VERSION 5.7 ;
  NOWIREEXTENSIONATPIN ON ;
  DIVIDERCHAR "/" ;
  BUSBITCHARS "[]" ;
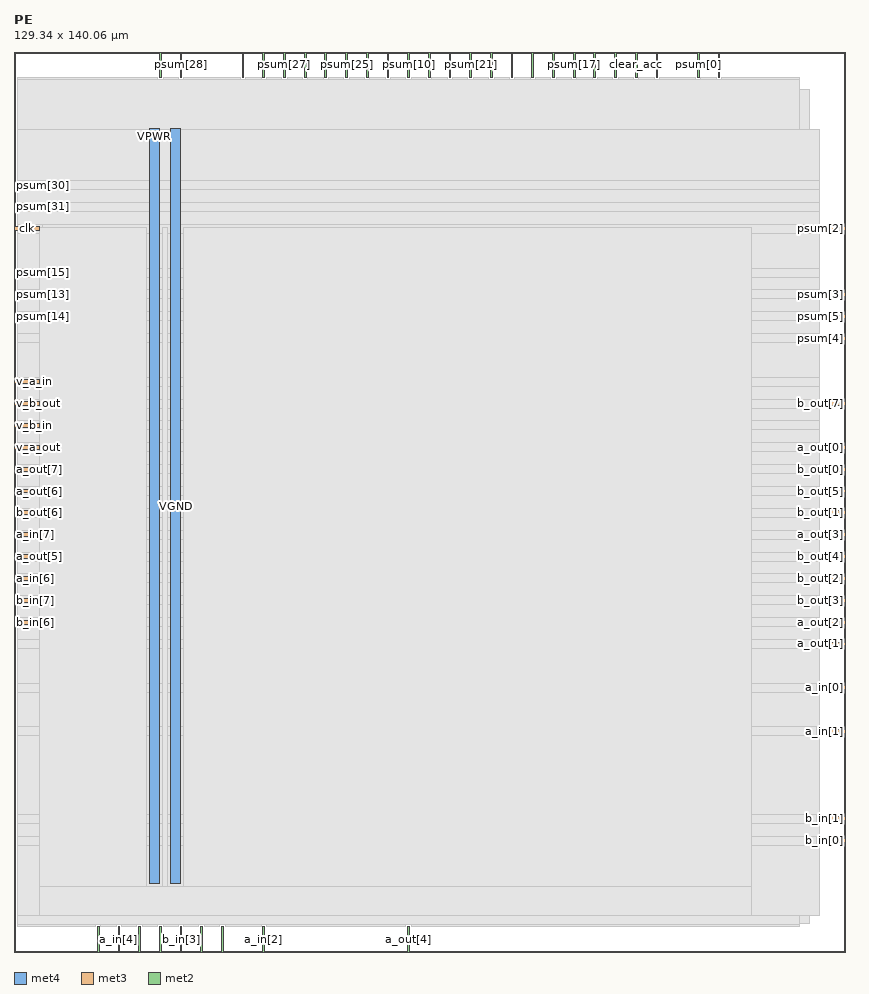
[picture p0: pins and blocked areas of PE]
MACRO PE
  CLASS BLOCK ;
  FOREIGN PE ;
  ORIGIN 0.000 0.000 ;
  SIZE 129.340 BY 140.060 ;
  PIN VGND
    DIRECTION INOUT ;
    USE GROUND ;
    PORT
      LAYER met4 ;
        RECT 24.340 10.640 25.940 128.080 ;
    END
  END VGND
  PIN VPWR
    DIRECTION INOUT ;
    USE POWER ;
    PORT
      LAYER met4 ;
        RECT 21.040 10.640 22.640 128.080 ;
    END
  END VPWR
  PIN a_in[0]
    DIRECTION INPUT ;
    USE SIGNAL ;
    ANTENNAGATEAREA 0.196500 ;
    PORT
      LAYER met3 ;
        RECT 125.340 40.840 129.340 41.440 ;
    END
  END a_in[0]
  PIN a_in[1]
    DIRECTION INPUT ;
    USE SIGNAL ;
    ANTENNAGATEAREA 0.196500 ;
    PORT
      LAYER met3 ;
        RECT 125.340 34.040 129.340 34.640 ;
    END
  END a_in[1]
  PIN a_in[2]
    DIRECTION INPUT ;
    USE SIGNAL ;
    ANTENNAGATEAREA 0.196500 ;
    PORT
      LAYER met2 ;
        RECT 38.730 0.000 39.010 4.000 ;
    END
  END a_in[2]
  PIN a_in[3]
    DIRECTION INPUT ;
    USE SIGNAL ;
    ANTENNAGATEAREA 0.196500 ;
    PORT
      LAYER met2 ;
        RECT 12.970 0.000 13.250 4.000 ;
    END
  END a_in[3]
  PIN a_in[4]
    DIRECTION INPUT ;
    USE SIGNAL ;
    ANTENNAGATEAREA 0.196500 ;
    PORT
      LAYER met2 ;
        RECT 16.190 0.000 16.470 4.000 ;
    END
  END a_in[4]
  PIN a_in[5]
    DIRECTION INPUT ;
    USE SIGNAL ;
    ANTENNAGATEAREA 0.213000 ;
    PORT
      LAYER met2 ;
        RECT 19.410 0.000 19.690 4.000 ;
    END
  END a_in[5]
  PIN a_in[6]
    DIRECTION INPUT ;
    USE SIGNAL ;
    ANTENNAGATEAREA 0.495000 ;
    PORT
      LAYER met3 ;
        RECT 0.000 57.840 4.000 58.440 ;
    END
  END a_in[6]
  PIN a_in[7]
    DIRECTION INPUT ;
    USE SIGNAL ;
    ANTENNAGATEAREA 0.196500 ;
    PORT
      LAYER met3 ;
        RECT 0.000 64.640 4.000 65.240 ;
    END
  END a_in[7]
  PIN a_out[0]
    DIRECTION OUTPUT ;
    USE SIGNAL ;
    ANTENNADIFFAREA 0.445500 ;
    PORT
      LAYER met3 ;
        RECT 125.340 78.240 129.340 78.840 ;
    END
  END a_out[0]
  PIN a_out[1]
    DIRECTION OUTPUT ;
    USE SIGNAL ;
    ANTENNADIFFAREA 0.445500 ;
    PORT
      LAYER met3 ;
        RECT 125.340 47.640 129.340 48.240 ;
    END
  END a_out[1]
  PIN a_out[2]
    DIRECTION OUTPUT ;
    USE SIGNAL ;
    ANTENNADIFFAREA 0.445500 ;
    PORT
      LAYER met3 ;
        RECT 125.340 51.040 129.340 51.640 ;
    END
  END a_out[2]
  PIN a_out[3]
    DIRECTION OUTPUT ;
    USE SIGNAL ;
    ANTENNADIFFAREA 0.445500 ;
    PORT
      LAYER met3 ;
        RECT 125.340 64.640 129.340 65.240 ;
    END
  END a_out[3]
  PIN a_out[4]
    DIRECTION OUTPUT ;
    USE SIGNAL ;
    ANTENNADIFFAREA 0.445500 ;
    PORT
      LAYER met2 ;
        RECT 61.270 0.000 61.550 4.000 ;
    END
  END a_out[4]
  PIN a_out[5]
    DIRECTION OUTPUT ;
    USE SIGNAL ;
    ANTENNADIFFAREA 0.445500 ;
    PORT
      LAYER met3 ;
        RECT 0.000 61.240 4.000 61.840 ;
    END
  END a_out[5]
  PIN a_out[6]
    DIRECTION OUTPUT ;
    USE SIGNAL ;
    ANTENNADIFFAREA 0.445500 ;
    PORT
      LAYER met3 ;
        RECT 0.000 71.440 4.000 72.040 ;
    END
  END a_out[6]
  PIN a_out[7]
    DIRECTION OUTPUT ;
    USE SIGNAL ;
    ANTENNADIFFAREA 0.445500 ;
    PORT
      LAYER met3 ;
        RECT 0.000 74.840 4.000 75.440 ;
    END
  END a_out[7]
  PIN b_in[0]
    DIRECTION INPUT ;
    USE SIGNAL ;
    ANTENNAGATEAREA 0.196500 ;
    PORT
      LAYER met3 ;
        RECT 125.340 17.040 129.340 17.640 ;
    END
  END b_in[0]
  PIN b_in[1]
    DIRECTION INPUT ;
    USE SIGNAL ;
    ANTENNAGATEAREA 0.213000 ;
    PORT
      LAYER met3 ;
        RECT 125.340 20.440 129.340 21.040 ;
    END
  END b_in[1]
  PIN b_in[2]
    DIRECTION INPUT ;
    USE SIGNAL ;
    ANTENNAGATEAREA 0.213000 ;
    PORT
      LAYER met2 ;
        RECT 22.630 0.000 22.910 4.000 ;
    END
  END b_in[2]
  PIN b_in[3]
    DIRECTION INPUT ;
    USE SIGNAL ;
    ANTENNAGATEAREA 0.196500 ;
    PORT
      LAYER met2 ;
        RECT 25.850 0.000 26.130 4.000 ;
    END
  END b_in[3]
  PIN b_in[4]
    DIRECTION INPUT ;
    USE SIGNAL ;
    ANTENNAGATEAREA 0.196500 ;
    PORT
      LAYER met2 ;
        RECT 29.070 0.000 29.350 4.000 ;
    END
  END b_in[4]
  PIN b_in[5]
    DIRECTION INPUT ;
    USE SIGNAL ;
    ANTENNAGATEAREA 0.196500 ;
    PORT
      LAYER met2 ;
        RECT 32.290 0.000 32.570 4.000 ;
    END
  END b_in[5]
  PIN b_in[6]
    DIRECTION INPUT ;
    USE SIGNAL ;
    ANTENNAGATEAREA 0.196500 ;
    PORT
      LAYER met3 ;
        RECT 0.000 51.040 4.000 51.640 ;
    END
  END b_in[6]
  PIN b_in[7]
    DIRECTION INPUT ;
    USE SIGNAL ;
    ANTENNAGATEAREA 0.196500 ;
    PORT
      LAYER met3 ;
        RECT 0.000 54.440 4.000 55.040 ;
    END
  END b_in[7]
  PIN b_out[0]
    DIRECTION OUTPUT ;
    USE SIGNAL ;
    ANTENNADIFFAREA 0.445500 ;
    PORT
      LAYER met3 ;
        RECT 125.340 74.840 129.340 75.440 ;
    END
  END b_out[0]
  PIN b_out[1]
    DIRECTION OUTPUT ;
    USE SIGNAL ;
    ANTENNADIFFAREA 0.445500 ;
    PORT
      LAYER met3 ;
        RECT 125.340 68.040 129.340 68.640 ;
    END
  END b_out[1]
  PIN b_out[2]
    DIRECTION OUTPUT ;
    USE SIGNAL ;
    ANTENNADIFFAREA 0.445500 ;
    PORT
      LAYER met3 ;
        RECT 125.340 57.840 129.340 58.440 ;
    END
  END b_out[2]
  PIN b_out[3]
    DIRECTION OUTPUT ;
    USE SIGNAL ;
    ANTENNADIFFAREA 0.445500 ;
    PORT
      LAYER met3 ;
        RECT 125.340 54.440 129.340 55.040 ;
    END
  END b_out[3]
  PIN b_out[4]
    DIRECTION OUTPUT ;
    USE SIGNAL ;
    ANTENNADIFFAREA 0.445500 ;
    PORT
      LAYER met3 ;
        RECT 125.340 61.240 129.340 61.840 ;
    END
  END b_out[4]
  PIN b_out[5]
    DIRECTION OUTPUT ;
    USE SIGNAL ;
    ANTENNADIFFAREA 0.445500 ;
    PORT
      LAYER met3 ;
        RECT 125.340 71.440 129.340 72.040 ;
    END
  END b_out[5]
  PIN b_out[6]
    DIRECTION OUTPUT ;
    USE SIGNAL ;
    ANTENNADIFFAREA 0.445500 ;
    PORT
      LAYER met3 ;
        RECT 0.000 68.040 4.000 68.640 ;
    END
  END b_out[6]
  PIN b_out[7]
    DIRECTION OUTPUT ;
    USE SIGNAL ;
    ANTENNADIFFAREA 0.445500 ;
    PORT
      LAYER met3 ;
        RECT 125.340 85.040 129.340 85.640 ;
    END
  END b_out[7]
  PIN clear_acc
    DIRECTION INPUT ;
    USE SIGNAL ;
    ANTENNAGATEAREA 0.213000 ;
    PORT
      LAYER met2 ;
        RECT 96.690 136.060 96.970 140.060 ;
    END
  END clear_acc
  PIN clk
    DIRECTION INPUT ;
    USE SIGNAL ;
    ANTENNAGATEAREA 0.852000 ;
    PORT
      LAYER met3 ;
        RECT 0.000 112.240 4.000 112.840 ;
    END
  END clk
  PIN psum[0]
    DIRECTION OUTPUT ;
    USE SIGNAL ;
    ANTENNADIFFAREA 0.445500 ;
    PORT
      LAYER met2 ;
        RECT 106.350 136.060 106.630 140.060 ;
    END
  END psum[0]
  PIN psum[10]
    DIRECTION OUTPUT ;
    USE SIGNAL ;
    ANTENNADIFFAREA 0.445500 ;
    PORT
      LAYER met2 ;
        RECT 61.270 136.060 61.550 140.060 ;
    END
  END psum[10]
  PIN psum[11]
    DIRECTION OUTPUT ;
    USE SIGNAL ;
    ANTENNADIFFAREA 0.445500 ;
    PORT
      LAYER met2 ;
        RECT 48.390 136.060 48.670 140.060 ;
    END
  END psum[11]
  PIN psum[12]
    DIRECTION OUTPUT ;
    USE SIGNAL ;
    ANTENNADIFFAREA 0.445500 ;
    PORT
      LAYER met2 ;
        RECT 38.730 136.060 39.010 140.060 ;
    END
  END psum[12]
  PIN psum[13]
    DIRECTION OUTPUT ;
    USE SIGNAL ;
    ANTENNADIFFAREA 0.445500 ;
    PORT
      LAYER met3 ;
        RECT 0.000 102.040 4.000 102.640 ;
    END
  END psum[13]
  PIN psum[14]
    DIRECTION OUTPUT ;
    USE SIGNAL ;
    ANTENNADIFFAREA 0.445500 ;
    PORT
      LAYER met3 ;
        RECT 0.000 98.640 4.000 99.240 ;
    END
  END psum[14]
  PIN psum[15]
    DIRECTION OUTPUT ;
    USE SIGNAL ;
    ANTENNADIFFAREA 0.445500 ;
    PORT
      LAYER met3 ;
        RECT 0.000 105.440 4.000 106.040 ;
    END
  END psum[15]
  PIN psum[16]
    DIRECTION OUTPUT ;
    USE SIGNAL ;
    ANTENNADIFFAREA 0.445500 ;
    PORT
      LAYER met2 ;
        RECT 93.470 136.060 93.750 140.060 ;
    END
  END psum[16]
  PIN psum[17]
    DIRECTION OUTPUT ;
    USE SIGNAL ;
    ANTENNADIFFAREA 0.445500 ;
    PORT
      LAYER met2 ;
        RECT 87.030 136.060 87.310 140.060 ;
    END
  END psum[17]
  PIN psum[18]
    DIRECTION OUTPUT ;
    USE SIGNAL ;
    ANTENNADIFFAREA 0.445500 ;
    PORT
      LAYER met2 ;
        RECT 90.250 136.060 90.530 140.060 ;
    END
  END psum[18]
  PIN psum[19]
    DIRECTION OUTPUT ;
    USE SIGNAL ;
    ANTENNADIFFAREA 0.445500 ;
    PORT
      LAYER met2 ;
        RECT 80.590 136.060 80.870 140.060 ;
    END
  END psum[19]
  PIN psum[1]
    DIRECTION OUTPUT ;
    USE SIGNAL ;
    ANTENNADIFFAREA 1.336500 ;
    PORT
      LAYER met2 ;
        RECT 109.570 136.060 109.850 140.060 ;
    END
  END psum[1]
  PIN psum[20]
    DIRECTION OUTPUT ;
    USE SIGNAL ;
    ANTENNADIFFAREA 0.445500 ;
    PORT
      LAYER met2 ;
        RECT 67.710 136.060 67.990 140.060 ;
    END
  END psum[20]
  PIN psum[21]
    DIRECTION OUTPUT ;
    USE SIGNAL ;
    ANTENNADIFFAREA 0.445500 ;
    PORT
      LAYER met2 ;
        RECT 70.930 136.060 71.210 140.060 ;
    END
  END psum[21]
  PIN psum[22]
    DIRECTION OUTPUT ;
    USE SIGNAL ;
    ANTENNADIFFAREA 0.445500 ;
    PORT
      LAYER met2 ;
        RECT 64.490 136.060 64.770 140.060 ;
    END
  END psum[22]
  PIN psum[23]
    DIRECTION OUTPUT ;
    USE SIGNAL ;
    ANTENNADIFFAREA 0.445500 ;
    PORT
      LAYER met2 ;
        RECT 58.050 136.060 58.330 140.060 ;
    END
  END psum[23]
  PIN psum[24]
    DIRECTION OUTPUT ;
    USE SIGNAL ;
    ANTENNADIFFAREA 0.445500 ;
    PORT
      LAYER met2 ;
        RECT 54.830 136.060 55.110 140.060 ;
    END
  END psum[24]
  PIN psum[25]
    DIRECTION OUTPUT ;
    USE SIGNAL ;
    ANTENNADIFFAREA 0.445500 ;
    PORT
      LAYER met2 ;
        RECT 51.610 136.060 51.890 140.060 ;
    END
  END psum[25]
  PIN psum[26]
    DIRECTION OUTPUT ;
    USE SIGNAL ;
    ANTENNADIFFAREA 0.445500 ;
    PORT
      LAYER met2 ;
        RECT 35.510 136.060 35.790 140.060 ;
    END
  END psum[26]
  PIN psum[27]
    DIRECTION OUTPUT ;
    USE SIGNAL ;
    ANTENNADIFFAREA 0.445500 ;
    PORT
      LAYER met2 ;
        RECT 41.950 136.060 42.230 140.060 ;
    END
  END psum[27]
  PIN psum[28]
    DIRECTION OUTPUT ;
    USE SIGNAL ;
    ANTENNADIFFAREA 0.445500 ;
    PORT
      LAYER met2 ;
        RECT 25.850 136.060 26.130 140.060 ;
    END
  END psum[28]
  PIN psum[29]
    DIRECTION OUTPUT ;
    USE SIGNAL ;
    ANTENNADIFFAREA 0.445500 ;
    PORT
      LAYER met2 ;
        RECT 22.630 136.060 22.910 140.060 ;
    END
  END psum[29]
  PIN psum[2]
    DIRECTION OUTPUT ;
    USE SIGNAL ;
    ANTENNADIFFAREA 0.445500 ;
    PORT
      LAYER met3 ;
        RECT 125.340 112.240 129.340 112.840 ;
    END
  END psum[2]
  PIN psum[30]
    DIRECTION OUTPUT ;
    USE SIGNAL ;
    ANTENNADIFFAREA 0.445500 ;
    PORT
      LAYER met3 ;
        RECT 0.000 119.040 4.000 119.640 ;
    END
  END psum[30]
  PIN psum[31]
    DIRECTION OUTPUT ;
    USE SIGNAL ;
    ANTENNADIFFAREA 0.445500 ;
    PORT
      LAYER met3 ;
        RECT 0.000 115.640 4.000 116.240 ;
    END
  END psum[31]
  PIN psum[3]
    DIRECTION OUTPUT ;
    USE SIGNAL ;
    ANTENNADIFFAREA 0.445500 ;
    PORT
      LAYER met3 ;
        RECT 125.340 102.040 129.340 102.640 ;
    END
  END psum[3]
  PIN psum[4]
    DIRECTION OUTPUT ;
    USE SIGNAL ;
    ANTENNADIFFAREA 0.445500 ;
    PORT
      LAYER met3 ;
        RECT 125.340 95.240 129.340 95.840 ;
    END
  END psum[4]
  PIN psum[5]
    DIRECTION OUTPUT ;
    USE SIGNAL ;
    ANTENNADIFFAREA 0.445500 ;
    PORT
      LAYER met3 ;
        RECT 125.340 98.640 129.340 99.240 ;
    END
  END psum[5]
  PIN psum[6]
    DIRECTION OUTPUT ;
    USE SIGNAL ;
    ANTENNADIFFAREA 0.445500 ;
    PORT
      LAYER met2 ;
        RECT 99.910 136.060 100.190 140.060 ;
    END
  END psum[6]
  PIN psum[7]
    DIRECTION OUTPUT ;
    USE SIGNAL ;
    ANTENNADIFFAREA 0.445500 ;
    PORT
      LAYER met2 ;
        RECT 83.810 136.060 84.090 140.060 ;
    END
  END psum[7]
  PIN psum[8]
    DIRECTION OUTPUT ;
    USE SIGNAL ;
    ANTENNADIFFAREA 0.445500 ;
    PORT
      LAYER met2 ;
        RECT 77.370 136.060 77.650 140.060 ;
    END
  END psum[8]
  PIN psum[9]
    DIRECTION OUTPUT ;
    USE SIGNAL ;
    ANTENNADIFFAREA 0.445500 ;
    PORT
      LAYER met2 ;
        RECT 74.150 136.060 74.430 140.060 ;
    END
  END psum[9]
  PIN reset
    DIRECTION INPUT ;
    USE SIGNAL ;
    ANTENNAGATEAREA 0.213000 ;
    PORT
      LAYER met2 ;
        RECT 45.170 136.060 45.450 140.060 ;
    END
  END reset
  PIN v_a_in
    DIRECTION INPUT ;
    USE SIGNAL ;
    ANTENNAGATEAREA 0.213000 ;
    PORT
      LAYER met3 ;
        RECT 0.000 88.440 4.000 89.040 ;
    END
  END v_a_in
  PIN v_a_out
    DIRECTION OUTPUT ;
    USE SIGNAL ;
    ANTENNADIFFAREA 0.445500 ;
    PORT
      LAYER met3 ;
        RECT 0.000 78.240 4.000 78.840 ;
    END
  END v_a_out
  PIN v_b_in
    DIRECTION INPUT ;
    USE SIGNAL ;
    ANTENNAGATEAREA 0.213000 ;
    PORT
      LAYER met3 ;
        RECT 0.000 81.640 4.000 82.240 ;
    END
  END v_b_in
  PIN v_b_out
    DIRECTION OUTPUT ;
    USE SIGNAL ;
    ANTENNADIFFAREA 0.445500 ;
    PORT
      LAYER met3 ;
        RECT 0.000 85.040 4.000 85.640 ;
    END
  END v_b_out
  OBS
      LAYER nwell ;
        RECT 5.330 10.795 123.930 128.030 ;
      LAYER li1 ;
        RECT 5.520 10.795 123.740 127.925 ;
      LAYER met1 ;
        RECT 0.530 4.460 123.740 134.260 ;
      LAYER met2 ;
        RECT 0.550 135.780 22.350 136.060 ;
        RECT 23.190 135.780 25.570 136.060 ;
        RECT 26.410 135.780 35.230 136.060 ;
        RECT 36.070 135.780 38.450 136.060 ;
        RECT 39.290 135.780 41.670 136.060 ;
        RECT 42.510 135.780 44.890 136.060 ;
        RECT 45.730 135.780 48.110 136.060 ;
        RECT 48.950 135.780 51.330 136.060 ;
        RECT 52.170 135.780 54.550 136.060 ;
        RECT 55.390 135.780 57.770 136.060 ;
        RECT 58.610 135.780 60.990 136.060 ;
        RECT 61.830 135.780 64.210 136.060 ;
        RECT 65.050 135.780 67.430 136.060 ;
        RECT 68.270 135.780 70.650 136.060 ;
        RECT 71.490 135.780 73.870 136.060 ;
        RECT 74.710 135.780 77.090 136.060 ;
        RECT 77.930 135.780 80.310 136.060 ;
        RECT 81.150 135.780 83.530 136.060 ;
        RECT 84.370 135.780 86.750 136.060 ;
        RECT 87.590 135.780 89.970 136.060 ;
        RECT 90.810 135.780 93.190 136.060 ;
        RECT 94.030 135.780 96.410 136.060 ;
        RECT 97.250 135.780 99.630 136.060 ;
        RECT 100.470 135.780 106.070 136.060 ;
        RECT 106.910 135.780 109.290 136.060 ;
        RECT 110.130 135.780 122.270 136.060 ;
        RECT 0.550 4.280 122.270 135.780 ;
        RECT 0.550 4.000 12.690 4.280 ;
        RECT 13.530 4.000 15.910 4.280 ;
        RECT 16.750 4.000 19.130 4.280 ;
        RECT 19.970 4.000 22.350 4.280 ;
        RECT 23.190 4.000 25.570 4.280 ;
        RECT 26.410 4.000 28.790 4.280 ;
        RECT 29.630 4.000 32.010 4.280 ;
        RECT 32.850 4.000 38.450 4.280 ;
        RECT 39.290 4.000 60.990 4.280 ;
        RECT 61.830 4.000 122.270 4.280 ;
      LAYER met3 ;
        RECT 0.525 120.040 125.340 128.005 ;
        RECT 4.400 118.640 125.340 120.040 ;
        RECT 0.525 116.640 125.340 118.640 ;
        RECT 4.400 115.240 125.340 116.640 ;
        RECT 0.525 113.240 125.340 115.240 ;
        RECT 4.400 111.840 124.940 113.240 ;
        RECT 0.525 106.440 125.340 111.840 ;
        RECT 4.400 105.040 125.340 106.440 ;
        RECT 0.525 103.040 125.340 105.040 ;
        RECT 4.400 101.640 124.940 103.040 ;
        RECT 0.525 99.640 125.340 101.640 ;
        RECT 4.400 98.240 124.940 99.640 ;
        RECT 0.525 96.240 125.340 98.240 ;
        RECT 0.525 94.840 124.940 96.240 ;
        RECT 0.525 89.440 125.340 94.840 ;
        RECT 4.400 88.040 125.340 89.440 ;
        RECT 0.525 86.040 125.340 88.040 ;
        RECT 4.400 84.640 124.940 86.040 ;
        RECT 0.525 82.640 125.340 84.640 ;
        RECT 4.400 81.240 125.340 82.640 ;
        RECT 0.525 79.240 125.340 81.240 ;
        RECT 4.400 77.840 124.940 79.240 ;
        RECT 0.525 75.840 125.340 77.840 ;
        RECT 4.400 74.440 124.940 75.840 ;
        RECT 0.525 72.440 125.340 74.440 ;
        RECT 4.400 71.040 124.940 72.440 ;
        RECT 0.525 69.040 125.340 71.040 ;
        RECT 4.400 67.640 124.940 69.040 ;
        RECT 0.525 65.640 125.340 67.640 ;
        RECT 4.400 64.240 124.940 65.640 ;
        RECT 0.525 62.240 125.340 64.240 ;
        RECT 4.400 60.840 124.940 62.240 ;
        RECT 0.525 58.840 125.340 60.840 ;
        RECT 4.400 57.440 124.940 58.840 ;
        RECT 0.525 55.440 125.340 57.440 ;
        RECT 4.400 54.040 124.940 55.440 ;
        RECT 0.525 52.040 125.340 54.040 ;
        RECT 4.400 50.640 124.940 52.040 ;
        RECT 0.525 48.640 125.340 50.640 ;
        RECT 0.525 47.240 124.940 48.640 ;
        RECT 0.525 41.840 125.340 47.240 ;
        RECT 0.525 40.440 124.940 41.840 ;
        RECT 0.525 35.040 125.340 40.440 ;
        RECT 0.525 33.640 124.940 35.040 ;
        RECT 0.525 21.440 125.340 33.640 ;
        RECT 0.525 20.040 124.940 21.440 ;
        RECT 0.525 18.040 125.340 20.040 ;
        RECT 0.525 16.640 124.940 18.040 ;
        RECT 0.525 5.615 125.340 16.640 ;
      LAYER met4 ;
        RECT 3.975 10.240 20.640 112.705 ;
        RECT 23.040 10.240 23.940 112.705 ;
        RECT 26.340 10.240 114.705 112.705 ;
        RECT 3.975 5.615 114.705 10.240 ;
  END
END PE
END LIBRARY

